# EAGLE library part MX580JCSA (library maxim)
VOLTAGE REFERENCE

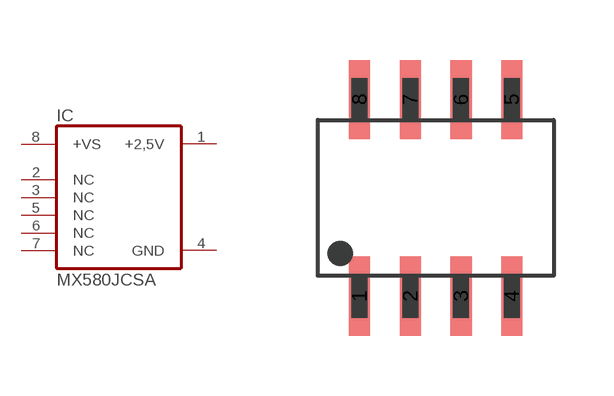
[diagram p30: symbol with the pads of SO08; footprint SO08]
Designator prefix IC

## MX580JCSA  [SO08]
1  +2,5V  out
2  NC  nc
3  NC  nc
4  GND  pwr
5  NC  nc
6  NC  nc
7  NC  nc
8  +VS  in

## Footprint SO08 (pad centres in mm)
Small Outline Package SOIC 150 mil
smd 0.53 x 1.98: 1 -1.905,-2.46; 2 -0.635,-2.46; 3 0.635,-2.46; 4 1.905,-2.46; 5 1.905,2.46; 6 0.635,2.46; 7 -0.635,2.46; 8 -1.905,2.46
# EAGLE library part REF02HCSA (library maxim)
VOLTAGE REFERENCE

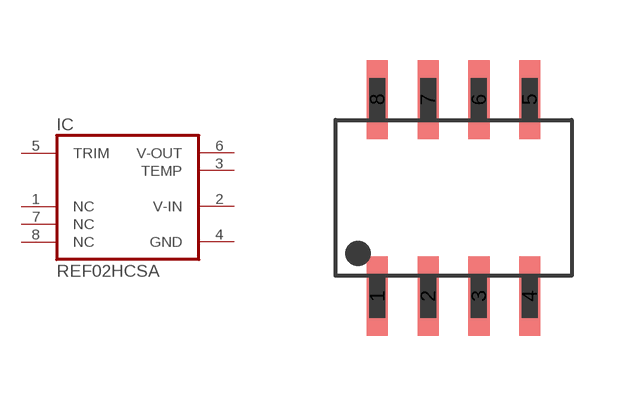
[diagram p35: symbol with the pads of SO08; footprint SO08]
Designator prefix IC

## REF02HCSA  [SO08]
1  NC  nc
2  V-IN  pwr
3  TEMP  out
4  GND  pwr
5  TRIM  in
6  V-OUT  out
7  NC  nc
8  NC  nc

## Footprint SO08 (pad centres in mm)
Small Outline Package SOIC 150 mil
smd 0.53 x 1.98: 1 -1.905,-2.46; 2 -0.635,-2.46; 3 0.635,-2.46; 4 1.905,-2.46; 5 1.905,2.46; 6 0.635,2.46; 7 -0.635,2.46; 8 -1.905,2.46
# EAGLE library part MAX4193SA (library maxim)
Step-up SWITCHING REGULATOR

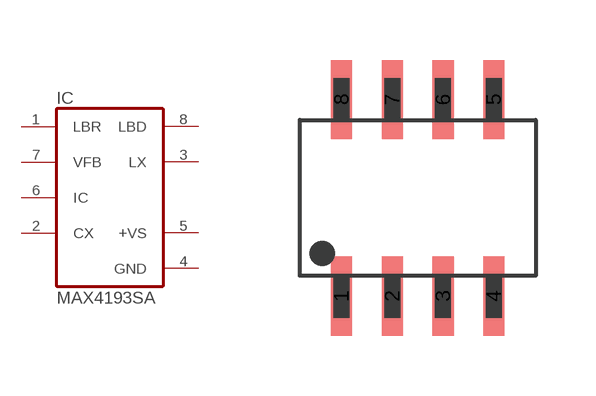
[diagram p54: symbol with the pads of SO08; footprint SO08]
Designator prefix IC

## MAX4193SA  [SO08]
1  LBR  in
2  CX  pas
3  LX  out
4  GND  pwr
5  +VS  pwr
6  IC  in
7  VFB  in
8  LBD  out

## Footprint SO08 (pad centres in mm)
Small Outline Package SOIC 150 mil
smd 0.53 x 1.98: 1 -1.905,-2.46; 2 -0.635,-2.46; 3 0.635,-2.46; 4 1.905,-2.46; 5 1.905,2.46; 6 0.635,2.46; 7 -0.635,2.46; 8 -1.905,2.46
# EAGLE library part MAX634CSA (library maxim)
SWITCHING REGULATOR

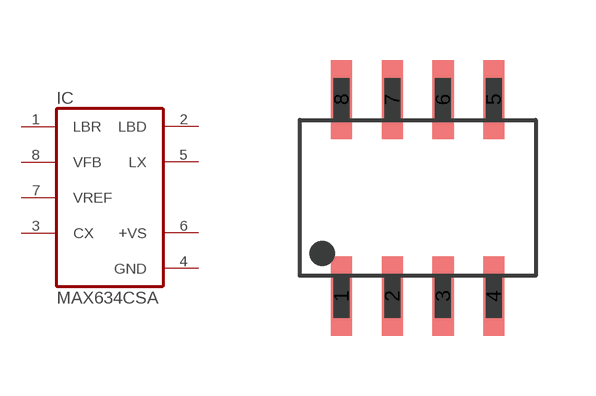
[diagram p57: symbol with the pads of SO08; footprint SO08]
Designator prefix IC

## MAX634CSA  [SO08]
1  LBR  in
2  LBD  out
3  CX  pas
4  GND  pwr
5  LX  out
6  +VS  pwr
7  VREF  in
8  VFB  in

## Footprint SO08 (pad centres in mm)
Small Outline Package SOIC 150 mil
smd 0.53 x 1.98: 1 -1.905,-2.46; 2 -0.635,-2.46; 3 0.635,-2.46; 4 1.905,-2.46; 5 1.905,2.46; 6 0.635,2.46; 7 -0.635,2.46; 8 -1.905,2.46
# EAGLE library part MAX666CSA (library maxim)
Positive VOLTAGE REGULATOR

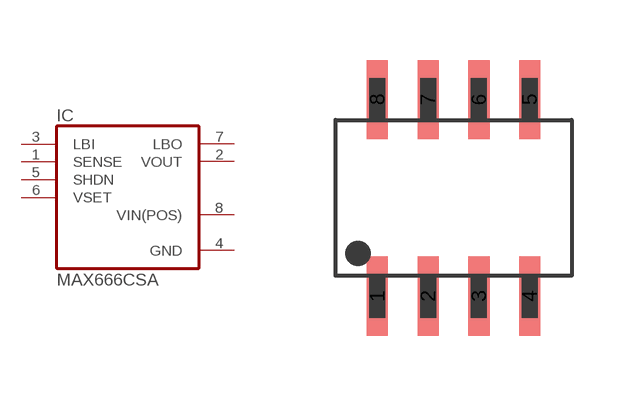
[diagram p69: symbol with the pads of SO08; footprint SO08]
Designator prefix IC

## MAX666CSA  [SO08]
1  SENSE  in
2  VOUT  out
3  LBI  in
4  GND  pwr
5  SHDN  in
6  VSET  in
7  LBO  out
8  VIN(POS)  pwr

## Footprint SO08 (pad centres in mm)
Small Outline Package SOIC 150 mil
smd 0.53 x 1.98: 1 -1.905,-2.46; 2 -0.635,-2.46; 3 0.635,-2.46; 4 1.905,-2.46; 5 1.905,2.46; 6 0.635,2.46; 7 -0.635,2.46; 8 -1.905,2.46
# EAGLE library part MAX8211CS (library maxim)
VOLTAGE MONITOR

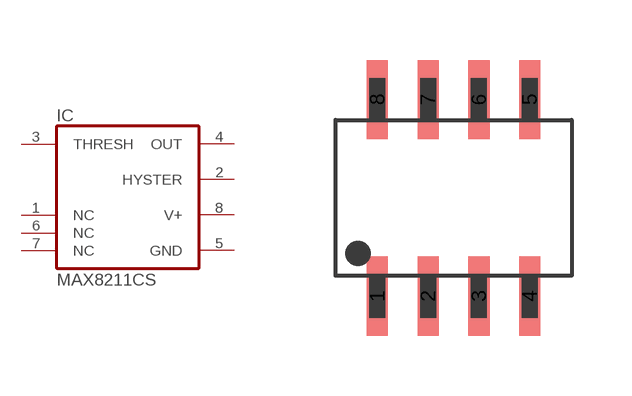
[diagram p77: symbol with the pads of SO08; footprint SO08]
Designator prefix IC

## MAX8211CS  [SO08]
1  NC  nc
2  HYSTER  out
3  THRESH  in
4  OUT  out
5  GND  pwr
6  NC  nc
7  NC  nc
8  V+  pwr

## Footprint SO08 (pad centres in mm)
Small Outline Package SOIC 150 mil
smd 0.53 x 1.98: 1 -1.905,-2.46; 2 -0.635,-2.46; 3 0.635,-2.46; 4 1.905,-2.46; 5 1.905,2.46; 6 0.635,2.46; 7 -0.635,2.46; 8 -1.905,2.46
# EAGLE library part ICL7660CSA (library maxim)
VOLTAGE CONVERTER

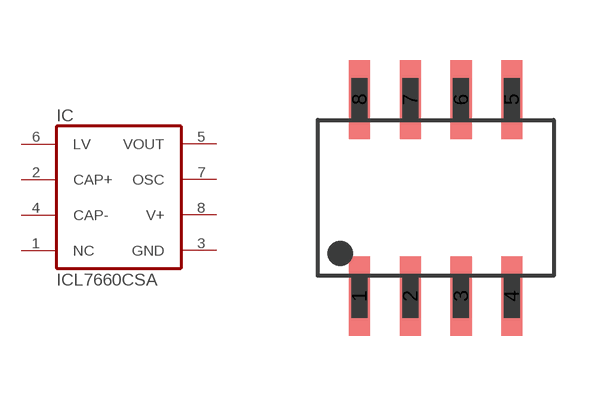
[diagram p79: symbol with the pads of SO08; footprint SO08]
Designator prefix IC

## ICL7660CSA  [SO08]
1  NC  nc
2  CAP+  pas
3  GND  pwr
4  CAP-  pas
5  VOUT  out
6  LV  pas
7  OSC  out
8  V+  pwr

## Footprint SO08 (pad centres in mm)
Small Outline Package SOIC 150 mil
smd 0.53 x 1.98: 1 -1.905,-2.46; 2 -0.635,-2.46; 3 0.635,-2.46; 4 1.905,-2.46; 5 1.905,2.46; 6 0.635,2.46; 7 -0.635,2.46; 8 -1.905,2.46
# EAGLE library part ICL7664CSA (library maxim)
Negative VOLTAGE REGULATOR

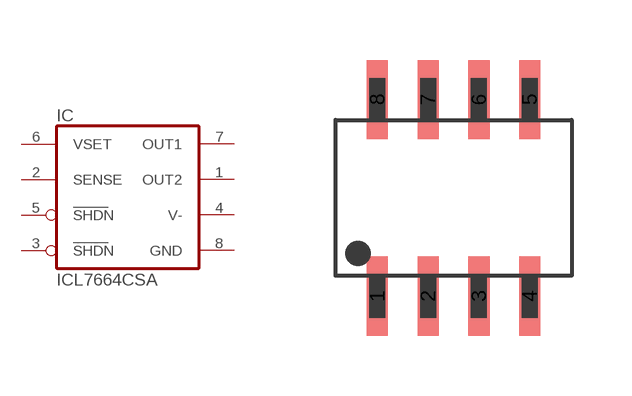
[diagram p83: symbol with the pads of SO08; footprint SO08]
Designator prefix IC

## ICL7664CSA  [SO08]
1  OUT2  out
2  SENSE  in
3  SHDN  in
4  V-  pwr
5  SHDN  in
6  VSET  in
7  OUT1  out
8  GND  pwr

## Footprint SO08 (pad centres in mm)
Small Outline Package SOIC 150 mil
smd 0.53 x 1.98: 1 -1.905,-2.46; 2 -0.635,-2.46; 3 0.635,-2.46; 4 1.905,-2.46; 5 1.905,2.46; 6 0.635,2.46; 7 -0.635,2.46; 8 -1.905,2.46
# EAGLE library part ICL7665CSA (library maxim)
UNDER/OVER VOLTAGE DETECTOR

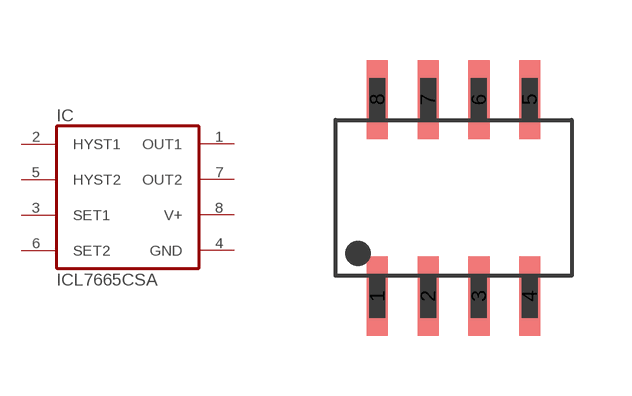
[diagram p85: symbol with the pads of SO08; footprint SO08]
Designator prefix IC

## ICL7665CSA  [SO08]
1  OUT1  out
2  HYST1  in
3  SET1  in
4  GND  pwr
5  HYST2  in
6  SET2  in
7  OUT2  out
8  V+  pwr

## Footprint SO08 (pad centres in mm)
Small Outline Package SOIC 150 mil
smd 0.53 x 1.98: 1 -1.905,-2.46; 2 -0.635,-2.46; 3 0.635,-2.46; 4 1.905,-2.46; 5 1.905,2.46; 6 0.635,2.46; 7 -0.635,2.46; 8 -1.905,2.46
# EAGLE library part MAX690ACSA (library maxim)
WATCHDOG

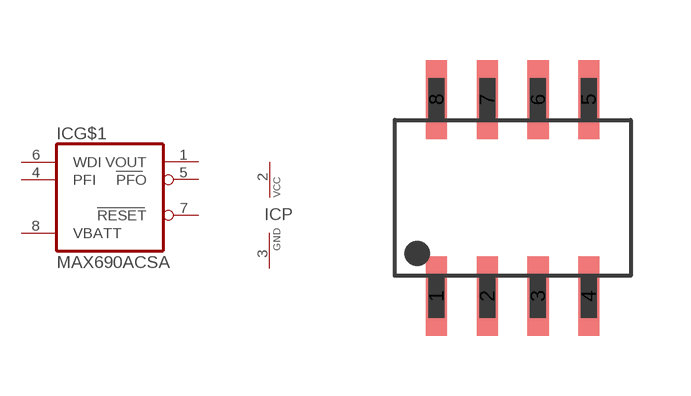
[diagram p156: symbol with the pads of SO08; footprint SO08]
Designator prefix IC; gates G$1=MAX690 P=VCC-GND

## MAX690ACSA  [SO08]
1  G$1:VOUT  out
2  P:VCC  pwr
3  P:GND  pwr
4  G$1:PFI  in
5  G$1:PFO  out
6  G$1:WDI  in
7  G$1:RESET  out
8  G$1:VBATT  in

## Footprint SO08 (pad centres in mm)
Small Outline Package SOIC 150 mil
smd 0.53 x 1.98: 1 -1.905,-2.46; 2 -0.635,-2.46; 3 0.635,-2.46; 4 1.905,-2.46; 5 1.905,2.46; 6 0.635,2.46; 7 -0.635,2.46; 8 -1.905,2.46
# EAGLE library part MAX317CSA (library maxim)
ANALOG SWITCH

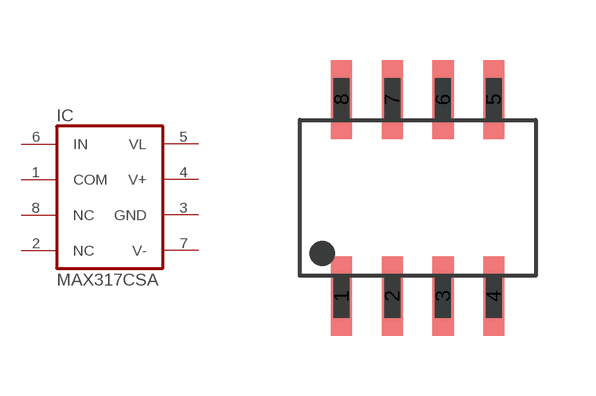
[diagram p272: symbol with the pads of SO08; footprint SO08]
Designator prefix IC

## MAX317CSA  [SO08]
1  COM  pas
2  NC  nc
3  GND  pwr
4  V+  pwr
5  VL  pwr
6  IN  in
7  V-  pwr
8  NC  pas

## Footprint SO08 (pad centres in mm)
Small Outline Package SOIC 150 mil
smd 0.53 x 1.98: 1 -1.905,-2.46; 2 -0.635,-2.46; 3 0.635,-2.46; 4 1.905,-2.46; 5 1.905,2.46; 6 0.635,2.46; 7 -0.635,2.46; 8 -1.905,2.46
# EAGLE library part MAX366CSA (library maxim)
Signal-line CIRCUIT PROTECTOR

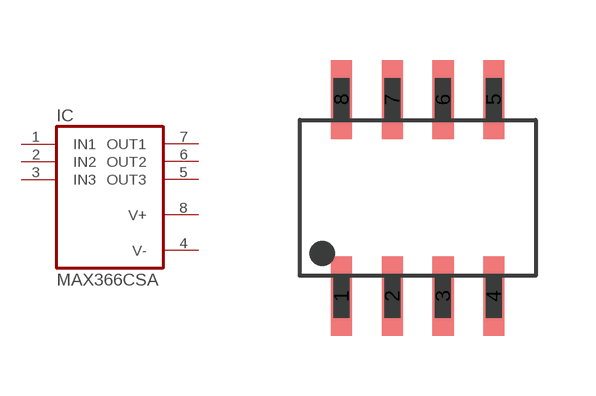
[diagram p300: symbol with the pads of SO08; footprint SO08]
Designator prefix IC

## MAX366CSA  [SO08]
1  IN1  pas
2  IN2  pas
3  IN3  pas
4  V-  pwr
5  OUT3  pas
6  OUT2  pas
7  OUT1  pas
8  V+  pwr

## Footprint SO08 (pad centres in mm)
Small Outline Package SOIC 150 mil
smd 0.53 x 1.98: 1 -1.905,-2.46; 2 -0.635,-2.46; 3 0.635,-2.46; 4 1.905,-2.46; 5 1.905,2.46; 6 0.635,2.46; 7 -0.635,2.46; 8 -1.905,2.46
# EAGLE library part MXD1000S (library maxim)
DELAY LINE

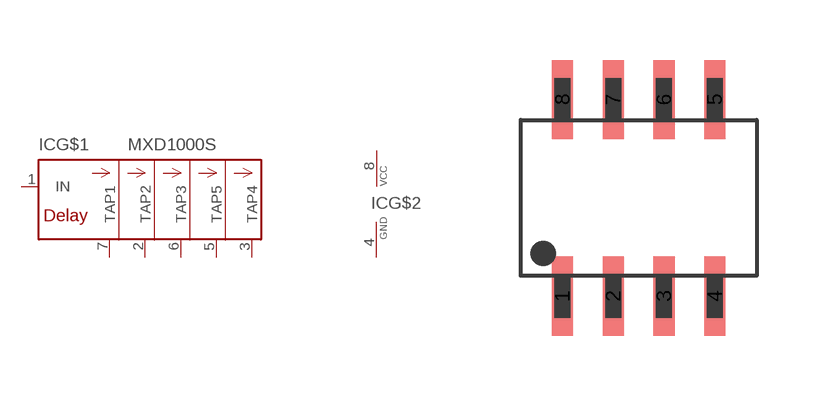
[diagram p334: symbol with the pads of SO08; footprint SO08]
Designator prefix IC; gates G$1=MXD1000 G$2=VCC-GND

## MXD1000S  [SO08]
1  G$1:IN  in
2  G$1:TAP2  out
3  G$1:TAP4  out
4  G$2:GND  pwr
5  G$1:TAP5  out
6  G$1:TAP3  out
7  G$1:TAP1  out
8  G$2:VCC  pwr

## Footprint SO08 (pad centres in mm)
Small Outline Package SOIC 150 mil
smd 0.53 x 1.98: 1 -1.905,-2.46; 2 -0.635,-2.46; 3 0.635,-2.46; 4 1.905,-2.46; 5 1.905,2.46; 6 0.635,2.46; 7 -0.635,2.46; 8 -1.905,2.46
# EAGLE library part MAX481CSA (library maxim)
RS485 TRANSEIVER

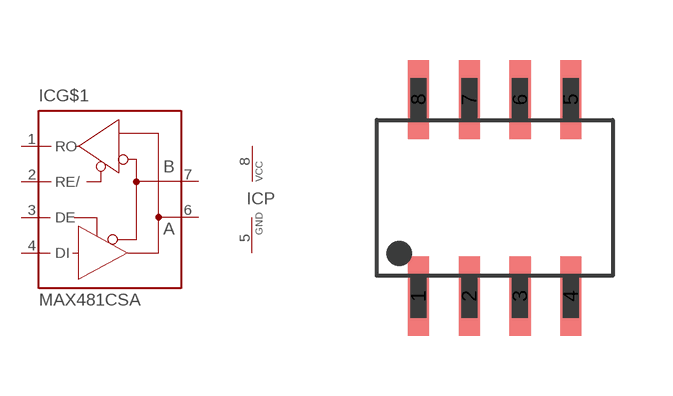
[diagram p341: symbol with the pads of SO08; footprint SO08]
Designator prefix IC; gates G$1=MAX481 P=VCC-GND

## MAX481CSA  [SO08]
1  G$1:RO  out
2  G$1:RE/  in
3  G$1:DE  in
4  G$1:DI  in
5  P:GND  pwr
6  G$1:A  pas
7  G$1:B  pas
8  P:VCC  pwr

## Footprint SO08 (pad centres in mm)
Small Outline Package SOIC 150 mil
smd 0.53 x 1.98: 1 -1.905,-2.46; 2 -0.635,-2.46; 3 0.635,-2.46; 4 1.905,-2.46; 5 1.905,2.46; 6 0.635,2.46; 7 -0.635,2.46; 8 -1.905,2.46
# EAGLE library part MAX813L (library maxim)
WATCHDOG

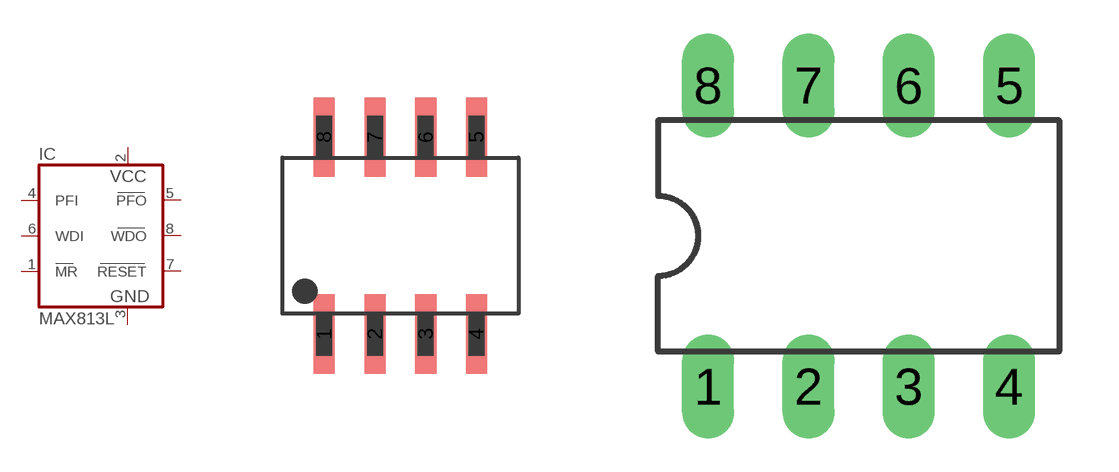
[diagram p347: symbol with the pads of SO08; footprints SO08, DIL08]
Designator prefix IC

## MAX813LCSA  [SO08]
1  MR  in
2  VCC  pwr
3  GND  pwr
4  PFI  in
5  PFO  out
6  WDI  in
7  RESET  out
8  WDO  out

## MAX813LCUA  [DIL08]
Pads as for SO08

## Footprint SO08 (pad centres in mm)
Small Outline Package SOIC 150 mil
smd 0.53 x 1.98: 1 -1.905,-2.46; 2 -0.635,-2.46; 3 0.635,-2.46; 4 1.905,-2.46; 5 1.905,2.46; 6 0.635,2.46; 7 -0.635,2.46; 8 -1.905,2.46

## Footprint DIL08 (pad centres in mm)
Dual In Line Package
drill 0.813 long: 1 -3.81,-3.81; 2 -1.27,-3.81; 3 1.27,-3.81; 4 3.81,-3.81; 5 3.81,3.81; 6 1.27,3.81; 7 -1.27,3.81; 8 -3.81,3.81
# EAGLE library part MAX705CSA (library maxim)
WATCHDOG

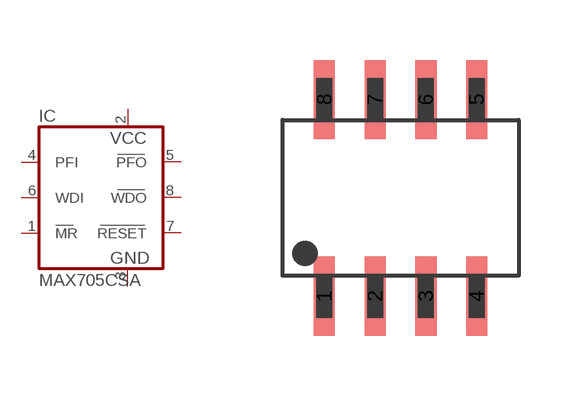
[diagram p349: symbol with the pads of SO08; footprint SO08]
Designator prefix IC

## MAX705CSA  [SO08]
1  MR  in
2  VCC  pwr
3  GND  pwr
4  PFI  in
5  PFO  out
6  WDI  in
7  RESET  out
8  WDO  out

## Footprint SO08 (pad centres in mm)
Small Outline Package SOIC 150 mil
smd 0.53 x 1.98: 1 -1.905,-2.46; 2 -0.635,-2.46; 3 0.635,-2.46; 4 1.905,-2.46; 5 1.905,2.46; 6 0.635,2.46; 7 -0.635,2.46; 8 -1.905,2.46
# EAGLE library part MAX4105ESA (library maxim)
OP AMP

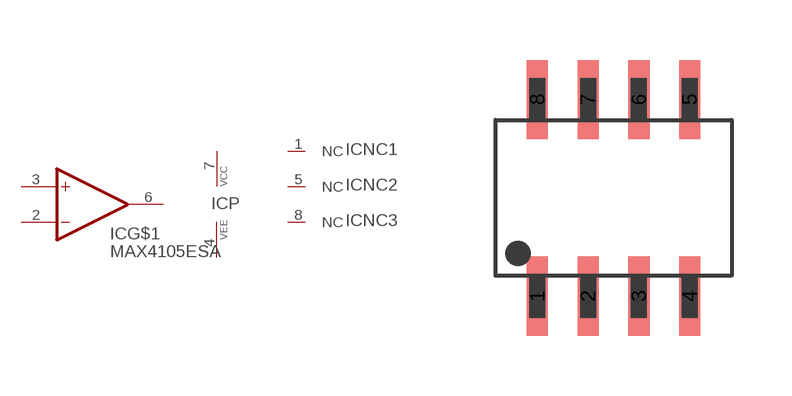
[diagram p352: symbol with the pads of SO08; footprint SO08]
Designator prefix IC; gates G$1=OP P=VCC-VEE NC1=NC NC2=NC NC3=NC

## MAX4105ESA  [SO08]
1  NC1:NC  nc
2  G$1:-IN  in
3  G$1:+IN  in
4  P:VEE  pwr
5  NC2:NC  nc
6  G$1:OUT  out
7  P:VCC  pwr
8  NC3:NC  nc

## Footprint SO08 (pad centres in mm)
Small Outline Package SOIC 150 mil
smd 0.53 x 1.98: 1 -1.905,-2.46; 2 -0.635,-2.46; 3 0.635,-2.46; 4 1.905,-2.46; 5 1.905,2.46; 6 0.635,2.46; 7 -0.635,2.46; 8 -1.905,2.46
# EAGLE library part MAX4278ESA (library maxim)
BUFFER

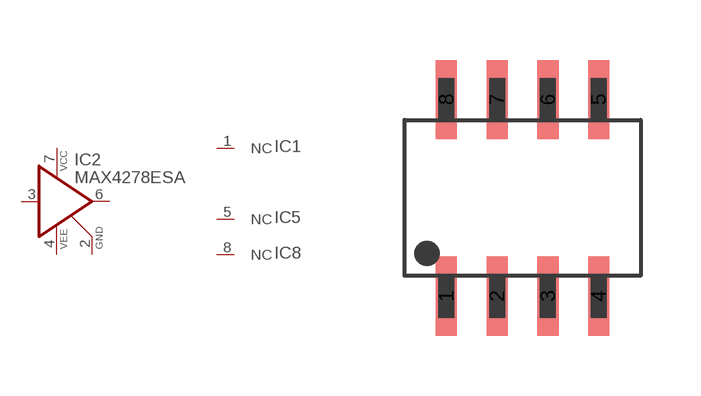
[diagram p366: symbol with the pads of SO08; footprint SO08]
Designator prefix IC; gates 1=NC 5=NC 8=NC 2=BUFF3P

## MAX4278ESA  [SO08]
1  1:NC  nc
2  2:GND  pwr
3  2:IN  in
4  2:VEE  pwr
5  5:NC  nc
6  2:OUT  out
7  2:VCC  pwr
8  8:NC  nc

## Footprint SO08 (pad centres in mm)
Small Outline Package SOIC 150 mil
smd 0.53 x 1.98: 1 -1.905,-2.46; 2 -0.635,-2.46; 3 0.635,-2.46; 4 1.905,-2.46; 5 1.905,2.46; 6 0.635,2.46; 7 -0.635,2.46; 8 -1.905,2.46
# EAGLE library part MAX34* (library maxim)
+5V, Fail-Safe, 40Mbps, Profibus RS-485/RS-422 Transceivers Source: MAX3465-MAX3469.pdf

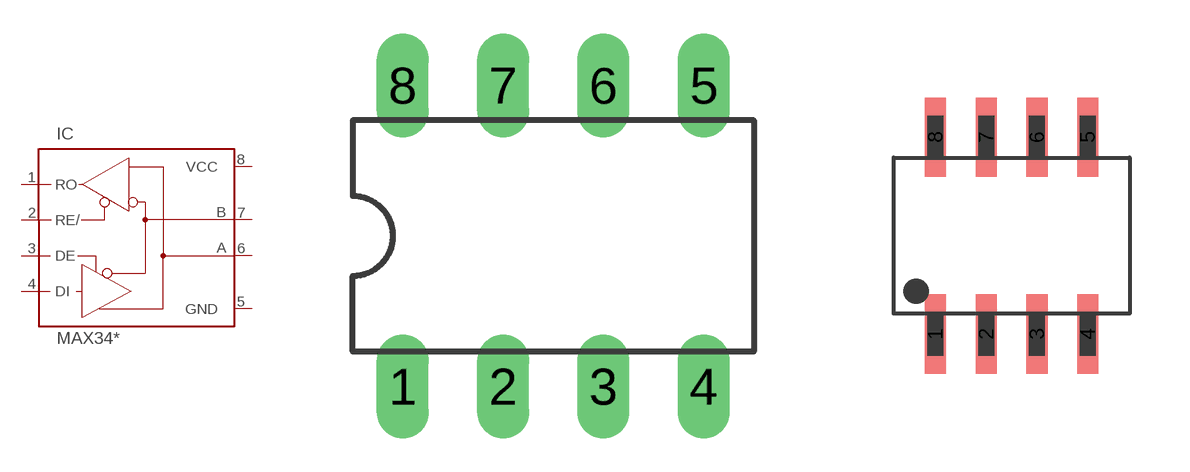
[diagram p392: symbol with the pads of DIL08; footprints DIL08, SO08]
Designator prefix IC

## MAX3468CPA, MAX3468EPA, MAX3469CPA, MAX3469EPA  [DIL08]
1  RO  out
2  RE/  in
3  DE  in
4  DI  in
5  GND  pwr
6  A  pas
7  B  pas
8  VCC  pwr

## MAX3468CSA, MAX3468ESA, MAX3469CSA, MAX3469ESA  [SO08]
Pads as for DIL08

## Footprint DIL08 (pad centres in mm)
Dual In Line Package
drill 0.813 long: 1 -3.81,-3.81; 2 -1.27,-3.81; 3 1.27,-3.81; 4 3.81,-3.81; 5 3.81,3.81; 6 1.27,3.81; 7 -1.27,3.81; 8 -3.81,3.81

## Footprint SO08 (pad centres in mm)
Small Outline Package SOIC 150 mil
smd 0.53 x 1.98: 1 -1.905,-2.46; 2 -0.635,-2.46; 3 0.635,-2.46; 4 1.905,-2.46; 5 1.905,2.46; 6 0.635,2.46; 7 -0.635,2.46; 8 -1.905,2.46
